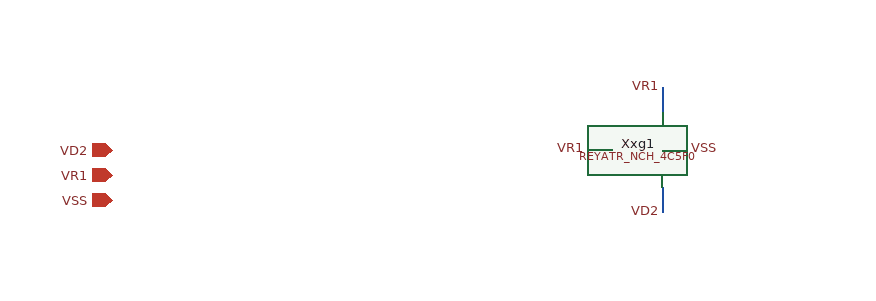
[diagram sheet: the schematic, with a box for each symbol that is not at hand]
v {xschem version=3.0.0 file_version=1.2 }
G {}
K {}
V {}
S {}
E {}
C {devices/iopin.sym} 0 0 0 0 {name=p0 lab=VD2}
C {devices/iopin.sym} 0 20 0 0 {name=p1 lab=VR1}
C {devices/iopin.sym} 0 40 0 0 {name=p2 lab=VSS}
C {REY_ATR_SKY130A/REYATR_NCH_4C5F0.sym} 400 0 0 0 {name=Xxg1}
N 440.0 -50.0 440.0 -30.0 {lab=VR1}
C {devices/lab_pin.sym} 440.0 -50.0 3 0 {name=l0 sig_type=std_logic lab=VR1 }
N 380.0 0.0 400.0 0.0 {lab=VR1}
C {devices/lab_pin.sym} 380.0 0.0 0 0 {name=l1 sig_type=std_logic lab=VR1 }
N 440.0 50.0 440.0 30.0 {lab=VD2}
C {devices/lab_pin.sym} 440.0 50.0 1 0 {name=l2 sig_type=std_logic lab=VD2 }
N 460.0 0.0 440.0 0.0 {lab=VSS}
C {devices/lab_pin.sym} 460.0 0.0 2 0 {name=l3 sig_type=std_logic lab=VSS }
